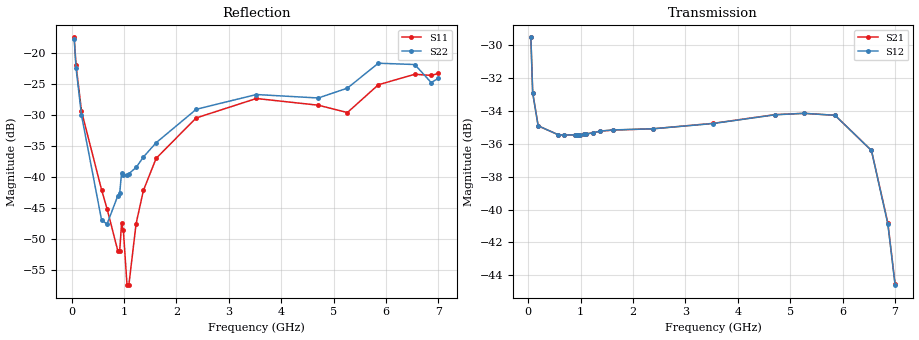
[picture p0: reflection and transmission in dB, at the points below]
! Integrated Device Technology
! Corporate Headquarters
! 6024 Silver Creek Valley Road
! San Jose, CA 95138  USA
! Phone:  1-408-284-8200
! Toll Free:  1-800-223-1366
! Webpage:  http://www.idt.com/
! Timing and RF Division
! 515 Groton Road, Suite 102
! Westford, MA 01886-6024
! Device:  F2258
! Description: Voltage Variable RF Attenuator
! Frequency:  50.0 -  6000.00 MHz
! Package:  3x3 mm Thin QFN Plastic Package: 16 pin
! Ports:  2 RF, 2 DC
!  Pin  1  = NC
!  Pin  2  = NC
!  Pin  3  = RF2  = Port 2
!  Pin  4  = GND
!  Pin  5  = Vdd
!  Pin  6  = NC
!  Pin  7  = VCTRL
!  Pin  8  = NC
!  Pin  9  = GND
!  Pin 10  = RF1  = Port 1
!  Pin 11  = NC
!  Pin 12  = NC
!  Pin 13  = NC
!  Pin 14  = NC
!  Pin 15  = NC
!  Pin 16  = NC
! Vcntrl:  2.330 Volts
! Vdd:  +3.300 Volts
! Current:  1.149 mA
! Data:  The device was measured on a the F2258 evaluation board which has
!  individual transmission lines to the RF pins.  Data was collected
!  using a calibrated network analyzer.  The evaluation board was
!  de-embedded using a TRL calibration technique.
!  The reference plane is the edge of the package pin.
! Misc:  SN 10
!  Action Tracker AT0285
! Date Measured:  2014-12-10
! Date:  2016-01-13  MJV
! Note:
!  Integrated Device Technology supplies this data as a sample of measured
!  data at the package pin for this product.  Your particular data for this
!  product may vary.
!  Data was taken at 25 degrees C.
!  Integrated Device Technology reserves the right to change this data at anytime.
!Freq_(GHz)  S11M_(dB)  S11P_(deg)  S21M_(dB)  S21P_(deg)  S12M_(dB)  S12P_(deg)  S22M_(dB)  S22P_(deg)
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# GHz S dB R 50
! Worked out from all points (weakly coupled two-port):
!   201 points, 50 MHz to 7 GHz, reference 50 ohm
!   highest |S21| = -29.53 dB at 50 MHz (marker M1); lowest = -44.5 dB at 7 GHz (marker M2)
!   lowest |S11| = -57.5 dB at 1.093 GHz (marker M3), VSWR 1.00, Z = 49.9 + j0.115 ohm
!   |S11| at or under -10 dB: start of sweep to end of sweep
!   |S22| runs from -47.8 to -17.8 dB; largest |S21 - S12| = 7.6e-05
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0.05  -17.56 -111.0  -29.53 -68.6  -29.53 -68.6  -17.81 -111.5
0.08475  -21.98 -107.5  -32.90 -48.8  -32.90 -48.8  -22.46 -108.0
0.189  -29.43 -109.4  -34.91 -24.8  -34.91 -24.8  -30.07 -111.1
0.57125  -42.07 -125.1  -35.45 -10.4  -35.45 -10.4  -46.93 -168.1
0.6755  -45.13 -132.1  -35.47 -9.4  -35.47 -9.4  -47.64 150.6
0.884  -51.98 165.8  -35.46 -8.4  -35.46 -8.4  -43.02 122.6
0.91875  -51.90 150.6  -35.46 -8.3  -35.45 -8.3  -42.62 120.6
0.9535  -47.50 -163.1  -35.47 -8.2  -35.46 -8.2  -39.36 125.0
0.98825  -48.65 -174.7  -35.45 -8.1  -35.45 -8.1  -39.64 122.7
1.05775  -57.45 153.7  -35.43 -7.9  -35.43 -7.9  -39.67 109.0
1.0925  -57.45 120.8  -35.41 -7.9  -35.41 -7.9  -39.51 105.0
1.2315  -47.53 47.1  -35.34 -7.9  -35.34 -7.9  -38.51 83.5
1.3705  -42.20 37.2  -35.24 -8.3  -35.23 -8.3  -36.82 69.9
1.61375  -37.03 32.9  -35.17 -9.5  -35.16 -9.5  -34.52 55.8
2.37825  -30.53 48.2  -35.09 -13.1  -35.09 -13.1  -29.14 44.8
3.525  -27.40 91.6  -34.76 -19.5  -34.77 -19.5  -26.76 68.3
4.7065  -28.48 95.7  -34.23 -28.7  -34.24 -28.6  -27.32 59.5
5.2625  -29.66 54.3  -34.15 -34.8  -34.15 -34.8  -25.73 22.2
5.85325  -25.19 29.9  -34.27 -45.4  -34.27 -45.4  -21.72 -1.9
6.54825  -23.50 45.0  -36.41 -66.3  -36.41 -66.3  -21.93 -37.1
6.861  -23.68 69.8  -40.81 -73.2  -40.88 -73.0  -24.83 -90.2
7  -23.37 84.5  -44.54 -61.4  -44.60 -60.9  -24.15 -130.1
